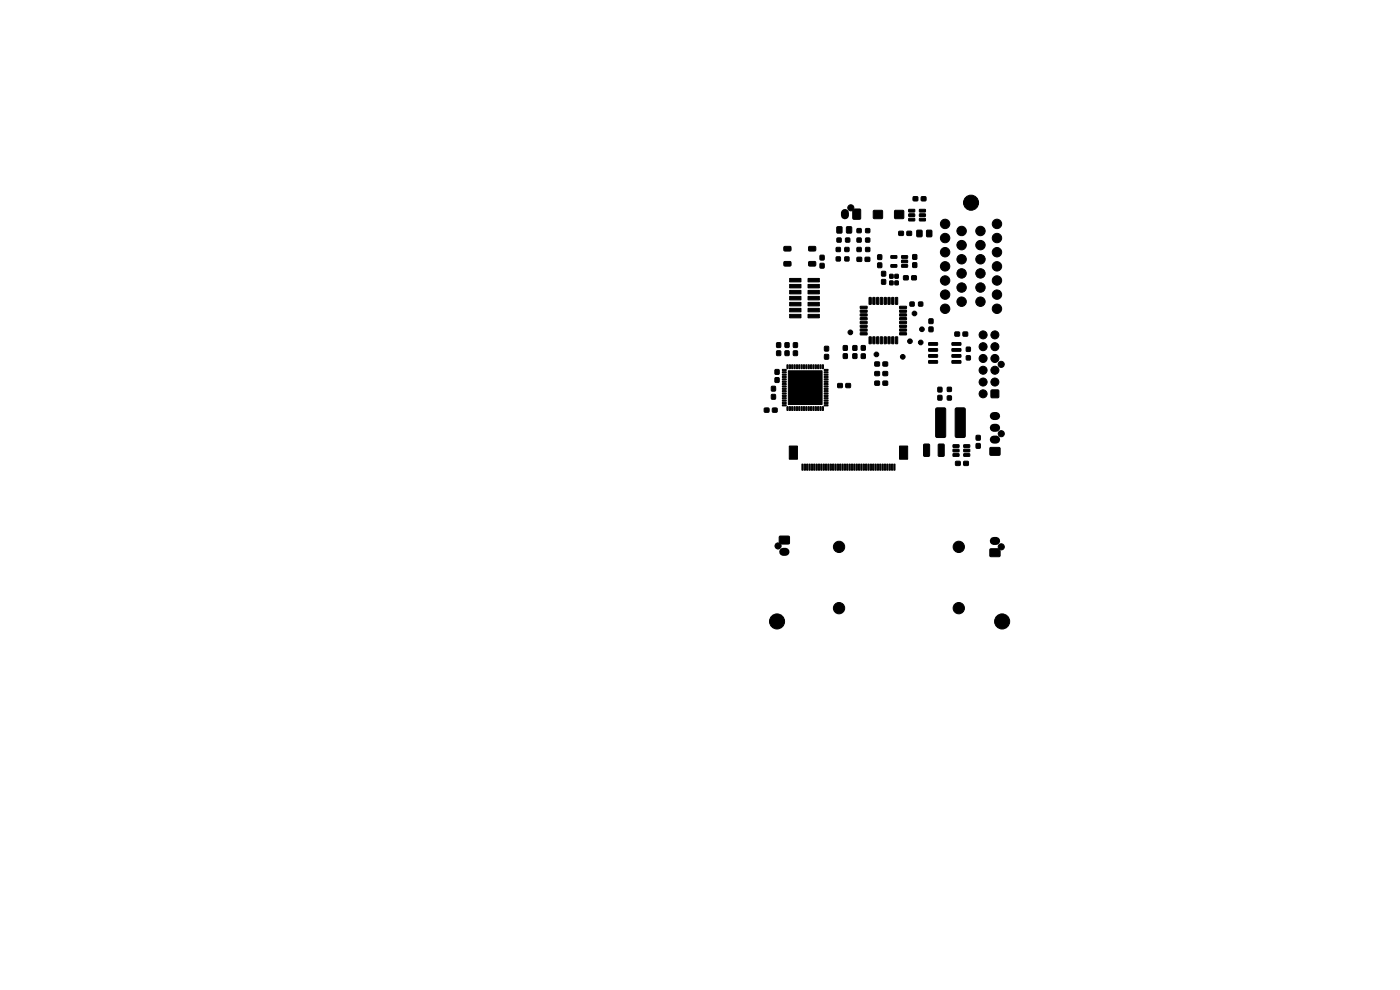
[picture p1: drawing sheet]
<svg xmlns="http://www.w3.org/2000/svg" width="297mm" height="210mm" viewBox="0 0 297 210" stroke-linecap="round" stroke-linejoin="round" font-family="sans-serif">
<g fill="#000" stroke="#000" stroke-width=".21">
<path d="M166.3 55.5h1.4l.1 .2v.6l-.2 .2-1.2-.1-.1-.2zM166.3 52.3h1.4l.1 .2v.6l-.2 .2-1.2-.1-.1-.2zM167.5 59.1h2.4v.7h-2.4zM171.6 55.5h1.3l.2 .2v.6l-.3 .2-1.1-.1-.2-.2zM171.6 52.3h1.3l.2 .2v.6l-.3 .2-1.1-.1-.2-.2zM171.4 59.1h2.4v.7h-2.4zM174 55.9h.8v.9h-.8zM174 54.2h.8v.9h-.8zM177.4 52.5h.9v.8h-.9zM177.6 48.1h1v1.3h-1zM177.6 50.5h.8v.8h-.8zM177.4 54.5h.9v.8h-.9z"/>
<path d="M179.2 52.5h.9v.8h-.9zM179.4 50.5h.8v.8h-.8zM179.6 48.1h1v1.3h-1zM179.2 54.5h.9v.8h-.9zM181.8 50.5h.9v.8h-.9zM181.8 54.6h1v.8h-1zM181 44.7l.4-.4 1.1 .1v2.1h-1.5zM181.8 52.5h.9v.8h-.9zM181.8 48.5h.9v.8h-.9zM183.6 54.6h.9v.8h-.9zM183.7 50.5h.8v.8h-.8zM183.7 52.5h.8v.8h-.8z"/>
<path d="M183.7 48.5h.8v.8h-.8zM186.2 54.1h.8v.9h-.8zM186.2 55.8h.8v.9h-.8zM187 57.6h.9v.9h-.9zM185.3 44.7h1.9v1.6h-1.9zM188.8 58.2h.6v.8h-.6zM188.8 59.6h.6v.8h-.6zM189 54.3l1.2-.1 .1 .5-1.2 .1zM189 56.2l1.2-.1 .1 .5-1.2 .1zM189.9 59.6h.6v.8h-.6zM189.9 58.2h.6v.8h-.6zM190.7 49.1h.9v.8h-.9z"/>
<path d="M191.7 58.5h.9v.8h-.9zM189.8 44.7h1.9v1.6h-1.9zM192.4 49.1h1v.8h-1zM191.3 56.2l1.2-.1 .1 .5-1.3 .1zM191.3 55.2h1.2l.1 .5h-1.3zM191.3 54.3l1.2-.1 .1 .5-1.3 .1zM193.4 58.5h1v.8h-1zM193.7 41.8h1v.8h-1zM193.7 55.8h.8v.9h-.8zM193.7 54h.8v1h-.8zM192.8 44.4h1.2l.1 .5-1.3 .1zM192.8 45.4l1.2-.1 .1 .5-1.3 .1z"/>
<path d="M192.8 46.3h1.2l.1 .5-1.3 .1zM195.5 41.8h.9v.8h-.9zM194.5 48.9h1.1v1.3h-1.1zM195.1 46.3h1.2v.5l-1.2 .1zM195.1 45.4l1.2-.1v.5l-1.2 .1zM195.1 44.4h1.2v.5l-1.2 .1zM196.6 48.9h1v1.3h-1zM164.4 78.4h.9v1h-.9zM164.8 74.5h.8v.9h-.8zM164.8 72.7h.8v1h-.8zM166.6 74.5h.8v.9h-.8zM166.6 72.7h.8v1h-.8z"/>
<path d="M166 78.4h.8v.2h-.8zM166 78.9h.8v.2h-.8zM166 79.4h.8v.2h-.8zM166 79.9h.8v.2h-.8zM167 77.4h.2v.8h-.3zM167.2 78.7h7.2v7.1h-7.2zM167.5 77.4h.2v.8h-.3zM168 77.4h.2v.8h-.3zM168.3 74.5h.8v.9h-.8zM168.3 72.7h.8v1h-.8zM168.5 77.4h.2v.8h-.3zM169 77.4h.2v.8h-.3z"/>
<path d="M169.5 77.4h.2v.8h-.3zM167.5 66.7h2.4v.7h-2.4zM167.5 65.4h2.4v.8h-2.4zM167.5 64.1h2.4v.8h-2.4zM167.5 62.9h2.4v.7h-2.4zM167.5 61.6h2.4v.7h-2.4zM167.5 60.3h2.4v.8h-2.4zM170 77.4h.2v.8h-.3zM170.5 77.4h.2v.8h-.3zM171 77.4h.2v.8h-.3zM171.5 77.4h.2v.8h-.3zM172 77.4h.2v.8h-.3z"/>
<path d="M172.5 77.4h.2v.8h-.3zM173 77.4h.2v.8h-.3zM173.5 77.4h.2v.8h-.3zM171.4 66.7h2.4v.7h-2.4zM171.4 65.4h2.4v.8h-2.4zM171.4 64.1h2.4v.8h-2.4zM171.4 62.9h2.4v.7h-2.4zM171.4 61.6h2.4v.7h-2.4zM171.4 60.3h2.4v.8h-2.4zM174 77.4h.2v.8h-.3zM174.5 77.4h.2v.8h-.3zM174.9 75.2h.9v1h-.9z"/>
<path d="M174.9 73.5h.9v.9h-.9zM174.9 79.9h.7l.1 .2h-.8zM174.9 79.4h.7l.1 .2h-.8zM174.9 78.9h.7l.1 .2h-.8zM174.9 78.4h.7l.1 .2h-.8zM178.9 73.3h.8v1h-.8zM178.9 75.1h.8v.9h-.8zM181 73.3h.8v1h-.8zM181 75.1h.8v.9h-.8zM182.7 75.1h.8v.9h-.8zM182.7 73.3h.8v1h-.8zM182.5 65h1.4l.1 .4h-1.4z"/>
<path d="M182.5 65.8h1.4l.1 .4h-1.4zM182.5 66.6h1.4l.1 .4h-1.4zM182.5 67.4h1.4l.1 .4h-1.4zM182.5 68.2h1.4l.1 .4h-1.4zM182.5 69h1.4l.1 .4h-1.4zM182.5 69.8h1.4l.1 .4h-1.4zM182.5 70.6h1.4l.1 .4h-1.4zM184.4 63.1l.4 .1v1.4l-.4-.1zM184.4 71.5h.4v1.4h-.4zM185.2 63.1l.4 .1v1.4l-.4-.1zM185.2 71.5h.4v1.4h-.4zM186 63.1l.4 .1v1.4l-.4-.1z"/>
<path d="M186 71.5h.4v1.4h-.4zM185.6 78.8h.9v.9h-.9zM185.6 76.8h.9v.8h-.9zM186.8 63.1l.4 .1v1.4l-.4-.1zM186.8 71.5h.4v1.4h-.4zM187 59.3h.9v1h-.9zM187.6 63.1l.4 .1v1.4l-.4-.1zM187.6 71.5h.4v1.4h-.4zM187.3 78.8h1v.9h-1zM187.3 76.8h1v.8h-1zM188.4 63.1l.4 .1v1.4l-.4-.1zM188.4 71.5h.4v1.4h-.4z"/>
<path d="M189.2 63.1l.4 .1v1.4l-.4-.1zM189.2 71.5h.4v1.4h-.4zM190 63.1l.4 .1v1.4l-.4-.1zM190 71.5h.4v1.4h-.4zM190.9 70.6h1.3l.1 .4h-1.4zM190.9 69.8h1.3l.1 .4h-1.4zM190.9 69h1.3l.1 .4h-1.4zM190.9 68.2h1.3l.1 .4h-1.4zM190.9 67.4h1.3l.1 .4h-1.4zM190.9 66.6h1.3l.1 .4h-1.4zM190.9 65.8h1.3l.1 .4h-1.4zM190.9 65h1.3l.1 .4h-1.4z"/>
<path d="M193.1 64.1h.8v.8h-.8zM194.9 64.1h.8v.8h-.8zM197 72.7h1.8l.1 .5h-1.8zM197 74l1.8-.1 .1 .5-1.8 .1zM197 75.2h1.8l.1 .5-1.8 .1zM197 76.5h1.8l.1 .5-1.8 .1zM197.1 69.4h.8v.9h-.8zM197.1 67.7h.8v.9h-.8zM202 76.5h1.8l.1 .5-1.9 .1zM202 75.2h1.8l.1 .5-1.9 .1zM202 74l1.8-.1 .1 .5-1.9 .1zM202 72.7h1.8l.1 .5h-1.9z"/>
<path d="M202.6 70.5h.9v.8h-.9zM204.3 70.5h1v.8h-1zM205 73.7h.8v.8h-.8zM205 75.5h.8v.8h-.8zM162.2 86.6h.9v.8h-.9zM163.7 83.7h.8v.9h-.8zM163.7 82h.8v.9h-.8zM164.4 80.2h.9v.9h-.9zM163.9 86.6h.9v.8h-.9zM166 80.4h.8v.2h-.8zM166 80.9h.8v.2h-.8zM166 81.4h.8v.2h-.8z"/>
<path d="M166 81.9h.8v.2h-.8zM166 82.4h.8v.2h-.8zM166 82.9h.8v.2h-.8zM166 83.4h.8v.2h-.8zM166 83.9h.8v.2h-.8zM166 84.4h.8v.2h-.8zM166 84.9h.8v.2h-.8zM166 85.4h.8v.2h-.8zM166 85.9h.8v.2h-.8zM167 86.3h.2v.8l-.3-.1zM167.5 86.3h.2v.8l-.3-.1zM168 86.3h.2v.8l-.3-.1z"/>
<path d="M168.5 86.3h.2v.8l-.3-.1zM169 86.3h.2v.8l-.3-.1zM167.4 94.6h1.8v2.8h-1.8zM169.5 86.3h.2v.8l-.3-.1zM170 86.3h.2v.8l-.3-.1zM170.1 98.4h.3v1.3h-.3zM170.5 86.3h.2v.8l-.3-.1zM170.6 98.4h.3v1.3h-.3zM171 86.3h.2v.8l-.3-.1zM171.1 98.4h.3v1.3h-.3zM171.5 86.3h.2v.8l-.3-.1zM171.6 98.4h.3v1.3h-.3z"/>
<path d="M172 86.3h.2v.8l-.3-.1zM172.1 98.4h.3v1.3h-.3zM172.5 86.3h.2v.8l-.3-.1zM172.6 98.4h.3v1.3h-.3zM173 86.3h.2v.8l-.3-.1zM173.1 98.4h.3v1.3h-.3zM173.5 86.3h.2v.8l-.3-.1zM173.6 98.4h.3v1.3h-.3zM174 86.3h.2v.8l-.3-.1zM174.1 98.4h.3v1.3h-.3zM174.5 86.3h.2v.8l-.3-.1zM174.6 98.4h.3v1.3h-.3z"/>
<path d="M175.1 98.4h.3v1.3h-.3zM174.9 85.9h.7l.1 .2h-.8zM174.9 85.4h.7l.1 .2h-.8zM174.9 84.9h.7l.1 .2h-.8zM174.9 84.4h.7l.1 .2h-.8zM174.9 83.9h.7l.1 .2h-.8zM174.9 83.4h.7l.1 .2h-.8zM174.9 82.9h.7l.1 .2h-.8zM174.9 82.4h.7l.1 .2h-.8zM174.9 81.9h.7l.1 .2h-.8zM174.9 81.4h.7l.1 .2h-.8zM174.9 80.9h.7l.1 .2h-.8z"/>
<path d="M174.9 80.4h.7l.1 .2h-.8zM175.6 98.4h.3v1.3h-.3zM176.1 98.4h.3v1.3h-.3zM176.6 98.4h.3v1.3h-.3zM177.1 98.4h.3v1.3h-.3zM177.7 81.4h1v.8h-1zM177.6 98.4h.3v1.3h-.3zM178.1 98.4h.3v1.3h-.3zM178.6 98.4h.3v1.3h-.3zM179.1 98.4h.3v1.3h-.3zM179.5 81.4h.9v.8h-.9zM179.6 98.4h.3v1.3h-.3z"/>
<path d="M180.1 98.4h.3v1.3h-.3zM180.6 98.4h.3v1.3h-.3zM181.1 98.4h.3v1.3h-.3zM181.6 98.4h.3v1.3h-.3zM182.1 98.4h.3v1.3h-.3zM182.6 98.4h.3v1.3h-.3zM183.1 98.4h.3v1.3h-.3zM183.6 98.4h.3v1.3h-.3zM184.1 98.4h.3v1.3h-.3zM184.6 98.4h.3v1.3h-.3zM185.1 98.4h.3v1.3h-.3zM185.6 98.4h.3v1.3h-.3z"/>
<path d="M186.1 98.4h.3v1.3h-.3zM185.6 80.9h.9v.8h-.9zM186.6 98.4h.3v1.3h-.3zM187.1 98.4h.3v1.3h-.3zM187.6 98.4h.3v1.3h-.3zM187.3 80.9h1v.8h-1zM188.1 98.4h.3v1.3h-.3zM188.6 98.4h.3v1.3h-.3zM189.1 98.4h.3v1.3h-.3zM189.6 98.4h.3v1.3h-.3zM190.8 94.6h1.8v2.8h-1.8zM196 94.3l1-.1 .2 .1v2.3l-.1 .2h-.9l-.3-.1z"/>
<path d="M198.5 86.6l.3-.1h1.5l.3 .3v5.7l-.2 .3h-1.6l-.3-.2zM199 83.9h.8v.9h-.8zM199 82.2h.8v.9h-.8zM199.1 94.3l1-.1 .2 .1v2.3l-.1 .2h-.9l-.3-.1zM201 82.2h.8v.8h-.8zM201 84h.8v.8h-.8zM202.2 94.4l1.2-.1 .1 .5-1.3 .1zM202.2 95.3h1.2l.1 .5-1.3 .1zM202.2 96.3l1.2-.1 .1 .5-1.3 .1zM202.7 86.6l.3-.1h1.5l.3 .3v5.7l-.3 .3h-1.5l-.4-.2zM202.7 97.9h1v.8h-1zM204.5 97.9h.9v.8h-.9z"/>
<path d="M204.5 96.3l1.2-.1v.5l-1.2 .1zM204.5 95.3h1.2v.5l-1.2 .1zM204.5 94.4l1.2-.1v.5l-1.2 .1zM207.1 94.1h.8v1h-.8zM207.1 92.4h.8v.9h-.8zM210.3 82.8h1.5v1.5h-1.5zM210 95h2.1v1.5h-2.1zM165.4 113.8h2v1.5h-1.8l-.3-.4zM210 116.5h1.8l.4 .4-.1 1.1h-2.1z"/>
<circle cx="180.5" cy="44.1" r=".65"/>
<circle cx="200.5" cy="53.5" r="1"/>
<circle cx="200.5" cy="59.5" r="1"/>
<circle cx="200.5" cy="50.5" r="1"/>
<circle cx="200.5" cy="56.5" r="1"/>
<circle cx="200.5" cy="47.5" r="1"/>
<circle cx="204" cy="55" r="1"/>
<circle cx="204" cy="49" r="1"/>
<circle cx="204" cy="52" r="1"/>
<circle cx="204" cy="58" r="1"/>
<circle cx="206" cy="43" r="1.6"/>
<circle cx="208" cy="49" r="1"/>
<circle cx="208" cy="55" r="1"/>
<circle cx="208" cy="52" r="1"/>
<circle cx="208" cy="58" r="1"/>
<circle cx="211.5" cy="59.5" r="1"/>
<circle cx="211.5" cy="53.5" r="1"/>
<circle cx="211.5" cy="50.5" r="1"/>
<circle cx="211.5" cy="56.5" r="1"/>
<circle cx="211.5" cy="47.5" r="1"/>
<circle cx="180.4" cy="70.5" r=".5"/>
<circle cx="185.9" cy="75.2" r=".5"/>
<circle cx="191.5" cy="75.7" r=".5"/>
<circle cx="193" cy="72.4" r=".5"/>
<circle cx="194" cy="66.5" r=".5"/>
<circle cx="195.3" cy="72.6" r=".5"/>
<circle cx="195.6" cy="69.9" r=".5"/>
<circle cx="200.5" cy="62.5" r="1"/>
<circle cx="200.5" cy="65.5" r="1"/>
<circle cx="204" cy="61" r="1"/>
<circle cx="204" cy="64" r="1"/>
<circle cx="208" cy="61" r="1"/>
<circle cx="208" cy="64" r="1"/>
<circle cx="208.6" cy="76" r=".85"/>
<circle cx="208.6" cy="73.5" r=".85"/>
<circle cx="208.6" cy="78.5" r=".85"/>
<circle cx="208.6" cy="71" r=".85"/>
<circle cx="211.1" cy="76" r=".85"/>
<circle cx="211.1" cy="73.5" r=".85"/>
<circle cx="211.1" cy="78.5" r=".85"/>
<circle cx="211.1" cy="71" r=".85"/>
<circle cx="211.5" cy="62.5" r="1"/>
<circle cx="211.5" cy="65.5" r="1"/>
<circle cx="212.4" cy="77.3" r=".65"/>
<circle cx="208.6" cy="81" r=".85"/>
<circle cx="208.6" cy="83.5" r=".85"/>
<circle cx="211.1" cy="81" r=".85"/>
<circle cx="212.4" cy="92" r=".65"/>
<circle cx="165.1" cy="115.8" r=".65"/>
<circle cx="178" cy="116" r="1.2"/>
<circle cx="203.4" cy="116" r="1.2"/>
<circle cx="212.4" cy="116" r=".65"/>
<circle cx="164.8" cy="131.8" r="1.6"/>
<circle cx="178" cy="129" r="1.2"/>
<circle cx="203.4" cy="129" r="1.2"/>
<circle cx="212.6" cy="131.8" r="1.6"/>
</g>
<path d="M179.2 45.2v.5M210.8 93.3h.5M210.8 90.8h.5M210.8 88.3h.5M166.1 117.1h.5M210.8 114.8h.5" fill="none" stroke="#000" stroke-width="1.7"/>
</svg>
